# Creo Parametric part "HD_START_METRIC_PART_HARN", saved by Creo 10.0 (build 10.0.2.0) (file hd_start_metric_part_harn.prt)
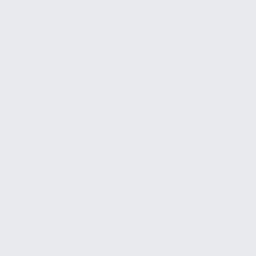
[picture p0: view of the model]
Units: hd_metric; MM, KILOGRAM, SECS
Materials in the file: DEFAULT

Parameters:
  DRW_UNITS = "METRIC"
  TOL_NAME = "MILLIMETERS"
  SUR = "6.3"
  LINEAR_TOL_0 = "1.0"
  PTC_WM_ITERATION = "0"
  PTC_WM_VERSION = ".0"
  PTC_WM_CREATED_ON = "29-Feb-16 09:18:37 AM"
  PTC_WM_MODIFIED_ON = "29-Feb-16 09:18:37 AM"
  PTC_MASTER_MATERIAL = "DEFAULT"

Created from: HD_START_METRIC_PART.PRT

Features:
  1. datum plane "SIDE"
  2. datum plane "TOP"
  3. datum plane "FRONT"
  4. coordinate system
  5. datum point "PT_ORIG"

Other named items: CS_DEF, COMB0001, CONFIDENTIALITY, ANNOT_LAYER_STATE0001, ANNOT_LAYER_STATE0002

Layers: AXES, COSMETIC, CS, CURVES, CURVES2, DATUMS, DEF_CS, DEF_DATUMS, PTS, SURFS

Notes: THIS CAD DOCUMENT AND ALL INFORMATION DISCLOSED HEREIN ARE THE EXCLUSIVE  | PROPERTY OF  | THE HARLEY-DAVIDSON MOTOR COMPANY ("H-D"), AND ARE SUBMITTED TO THE RECIPIENT  | ONLY ON A  | CONFIDENTIAL BASIS. IN CONSIDERATION OF RECEIVING THIS CAD DOCUMENT, THE  | RECIPIENT AGREES:  | (1) NOT TO USE THIS CAD DOCUMENT OR ANY OF THE INFORMATION DISCLOSED HEREIN TO  | PRODUCE  | ANY PRODUCT OR FOR ANY OTHER PURPOSE EXCEPT AS AUTHORIZED IN WRITING BY H-D;  | (2) NOT TO  | REPRODUCE THIS CAD DOCUMENT; (3) TO RETURN THIS CAD DOCUMENT TO H-D UPON  | REQUEST; AND  | (4) THAT NO DISCLOSURE OF THIS CAD DOCUMENT OR ANY OF THE INFORMATION DISCLOSED  | HEREIN  | WILL BE MADE TO ANY THIRD PARTY WITHOUT THE PRIOR WRITTEN CONSENT OF H-D.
